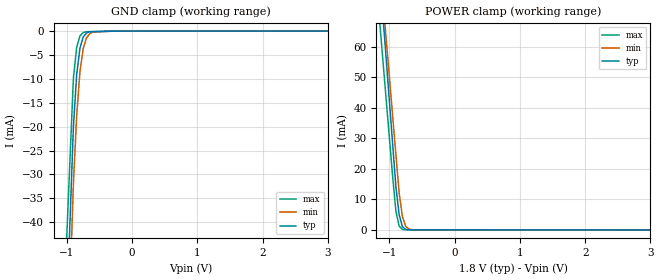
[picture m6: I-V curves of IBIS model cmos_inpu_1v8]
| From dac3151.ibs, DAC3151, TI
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[Model] cmos_inpu_1v8
Model_type Input
Vinl = 450.000mV
Vinh = 1.08000V
C_comp 865.000fF 865.000fF 865.000fF
| variable typ   min   max
[Voltage Range] 1.80000V 1.71000V 1.89000V
[POWER Clamp Reference] 1.80000V 1.71000V 1.89000V
[GND Clamp Reference] 0.00000V 0.00000V 0.00000V
[Temperature Range]   25   85   -40
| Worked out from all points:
|   GND clamp passes 1 mA (typ) near -0.74 V on its own axis
|   POWER clamp passes 1 mA (typ) near -0.80 V on its own axis
[GND Clamp]
-1.8V     -360.8mA   -403.8mA   -301.1mA
-900mV    -20.04mA   -32.01mA   -9.877mA
-850mV    -9.105mA   -17.76mA   -3.42mA
-800mV    -3.585mA   -8.546mA   -1.021mA
-750mV    -1.237mA   -3.657mA   -299.9uA
-700mV    -396.7uA   -1.438mA   -127uA
-650mV    -150.3uA   -566.3uA   -111.3uA
-600mV    -131.3uA   -187.9uA   -95.5uA
0V        0A         0A         0A
3.6V      0A         0A         0A
[POWER Clamp]
-1.8V     267.5mA    253.5mA    234.5mA
-1V       42.27mA    50.14mA    30.25mA
-950mV    28.2mA     37.43mA    17.49mA
-900mV    14.12mA    24.73mA    6.114mA
-850mV    4.945mA    12.02mA    1.212mA
-800mV    1.054mA    4.328mA    153.2uA
-750mV    162.6uA    1.145mA    18.7uA
-700mV    23.19uA    253.4uA    16.45uA
-650mV    19.88uA    47.7uA     14.19uA
3.6V      -25.72uA   -30.81uA   -26.35uA
